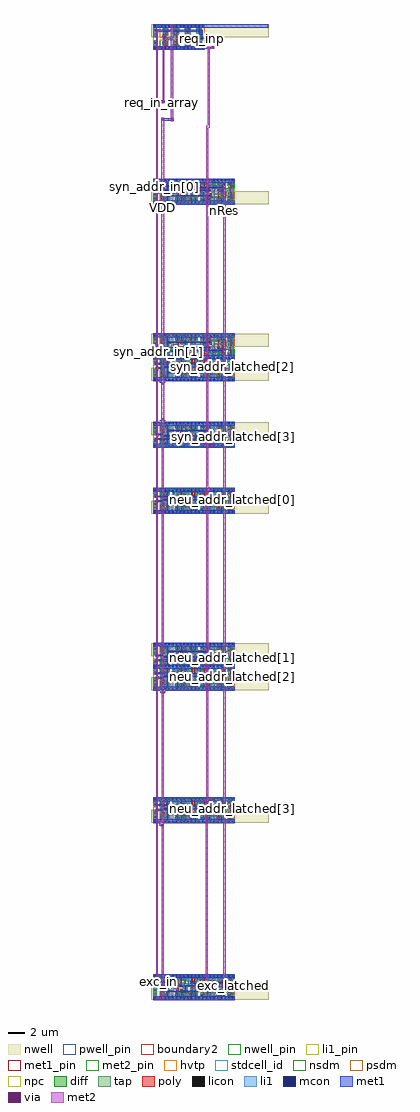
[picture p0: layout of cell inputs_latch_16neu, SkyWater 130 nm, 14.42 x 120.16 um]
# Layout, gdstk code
from math import pi, radians
import gdstk
lib = gdstk.Library(unit=1e-6, precision=1e-09)
def R(c, l, rs):  # rectangles x0, y0, x1, y1
    for r in rs: c.add(gdstk.rectangle(r[:2], r[2:], *l))
def A(c, l, x, y, w, h, nx, ny, dx, dy):  # array of equal rectangles
    R(c, l, [(x+i*dx, y+j*dy, x+i*dx+w, y+j*dy+h) for i in range(nx) for j in range(ny)])
def P(c, l, *ps):  # polygons
    for p in ps: c.add(gdstk.Polygon(p, *l))
nwell_pin = (64, 16)
nwell = (64, 20)
diff = (65, 20)
tap = (65, 44)
poly = (66, 20)
licon = (66, 44)
li1_pin = (67, 16)
li1 = (67, 20)
mcon = (67, 44)
met1_pin = (68, 16)
met1 = (68, 20)
via = (68, 44)
met2_pin = (69, 16)
met2 = (69, 20)
hvtp = (78, 44)
stdcell_id = (81, 4)
nsdm = (93, 44)
psdm = (94, 20)
npc = (95, 20)
pwell_pin = (122, 16)
boundary2 = (236, 0)

sky130_fd_sc_hd__dfrtp_1 = lib.new_cell('sky130_fd_sc_hd__dfrtp_1')
R(sky130_fd_sc_hd__dfrtp_1, nwell_pin, [(0.145,2.635,0.315,2.805)])
R(sky130_fd_sc_hd__dfrtp_1, nwell, [(-0.19,1.305,9.39,2.91)])
R(sky130_fd_sc_hd__dfrtp_1, diff, [(0.135,0.235,1.225,0.655), (0.135,1.815,1.225,2.455), (3.305,2.065,4.7,2.485)])
P(sky130_fd_sc_hd__dfrtp_1, diff, [(8,2.485),(5.015,2.485),(5.015,1.645),(5.695,1.645),(5.695,2.065),(8,2.065)],
  [(9.065,2.485),(8.325,2.485),(8.325,1.845),(8.405,1.845),(8.405,1.485),(9.065,1.485)],
  [(9.065,0.885),(8.405,0.885),(8.405,0.655),(8.295,0.655),(8.295,0.235),(9.065,0.235)],
  [(8.025,0.655),(6.165,0.655),(6.165,0.595),(5.315,0.595),(5.315,0.875),(4.645,0.875),(4.645,0.655),(3.285,0.655),(3.285,0.595),(2.49,0.595),(2.49,0.655),(1.565,0.655),(1.565,0.235),(8.025,0.235)],
  [(3.335,2.485),(1.89,2.485),(1.89,2.065),(3.33,2.065),(3.33,2.48),(3.335,2.48)])
R(sky130_fd_sc_hd__dfrtp_1, poly, [(3.875,0.105,4.025,1.515), (4.29,1.055,4.44,2.615), (3.805,1.445,4.08,1.775), (3.805,1.76,3.955,2.615)])
P(sky130_fd_sc_hd__dfrtp_1, poly, [(7.79,1.825),(7.73,1.825),(7.73,2.615),(7.58,2.615),(7.58,1.825),(7.52,1.825),(7.52,1.495),(7.615,1.495),(7.615,0.105),(7.765,0.105),(7.765,1.495),(7.79,1.495)],
  [(0.545,0.88),(0.38,0.88),(0.38,1.59),(0.545,1.59),(0.545,2.585),(0.395,2.585),(0.395,1.74),(0.23,1.74),(0.23,1.325),(0.11,1.325),(0.11,0.995),(0.23,0.995),(0.23,0.73),(0.395,0.73),(0.395,0.105),(0.545,0.105)],
  [(0.965,2.585),(0.815,2.585),(0.815,1.37),(0.59,1.37),(0.59,1.1),(0.815,1.1),(0.815,0.105),(0.965,0.105)],
  [(2.3,2.615),(2.15,2.615),(2.15,1.63),(1.655,1.63),(1.655,1.3),(2.09,1.3),(2.09,0.105),(2.24,0.105),(2.24,1.48),(2.3,1.48)],
  [(3.255,2.615),(3.105,2.615),(3.105,1.395),(2.565,1.395),(2.565,1.095),(2.45,1.095),(2.45,0.765),(2.565,0.765),(2.565,0.105),(2.715,0.105),(2.715,0.765),(2.72,0.765),(2.72,1.245),(3.255,1.245)],
  [(2.86,1.875),(2.76,1.875),(2.76,2.615),(2.61,2.615),(2.61,1.875),(2.53,1.875),(2.53,1.605),(2.86,1.605)],
  [(3.26,1.035),(2.93,1.035),(2.93,0.765),(3.045,0.765),(3.045,0.105),(3.195,0.105),(3.195,0.765),(3.26,0.765)],
  [(4.505,1.095),(4.235,1.095),(4.235,0.105),(4.385,0.105),(4.385,0.765),(4.505,0.765)],
  [(5.425,2.615),(5.275,2.615),(5.275,1.57),(4.895,1.57),(4.895,1.335),(4.715,1.335),(4.715,1.005),(4.895,1.005),(4.895,0.105),(5.045,0.105),(5.045,1.42),(5.425,1.42)],
  [(5.725,1.035),(5.39,1.035),(5.39,0.105),(5.54,0.105),(5.54,0.705),(5.725,0.705)],
  [(6.205,1.275),(6.085,1.275),(6.085,1.335),(6.02,1.335),(6.02,1.395),(5.92,1.395),(5.92,2.615),(5.77,2.615),(5.77,1.245),(5.875,1.245),(5.875,1.185),(5.935,1.185),(5.935,0.105),(6.085,0.105),(6.085,0.945),(6.205,0.945)],
  [(6.4,1.905),(6.35,1.905),(6.35,2.615),(6.2,2.615),(6.2,1.905),(6.13,1.905),(6.13,1.575),(6.4,1.575)],
  [(6.925,1.145),(6.77,1.145),(6.77,2.615),(6.62,2.615),(6.62,0.965),(6.415,0.965),(6.415,0.105),(6.565,0.105),(6.565,0.815),(6.925,0.815)],
  [(7.405,1.285),(7.31,1.285),(7.31,2.615),(7.16,2.615),(7.16,1.285),(7.135,1.285),(7.135,0.955),(7.16,0.955),(7.16,0.105),(7.31,0.105),(7.31,0.955),(7.405,0.955)],
  [(8.805,2.615),(8.655,2.615),(8.655,1.325),(8.51,1.325),(8.51,0.995),(8.655,0.995),(8.655,0.105),(8.805,0.105)])
R(sky130_fd_sc_hd__dfrtp_1, licon, [(1.625,0.275,1.795,0.445), (5.115,0.275,5.285,0.445), (6.725,0.275,6.895,0.445), (0.595,0.295,0.765,0.465), (4.555,0.295,4.725,0.465), (5.665,0.295,5.835,0.465), (8.435,0.295,8.605,0.465), (2.29,0.305,2.46,0.475), (2.825,0.305,2.995,0.475), (7.815,0.375,7.985,0.545), (0.175,0.425,0.345,0.595), (1.015,0.425,1.185,0.595), (8.855,0.545,9.025,0.715), (5.505,0.785,5.675,0.955), (3.01,0.815,3.18,0.985), (2.5,0.845,2.67,1.015), (4.285,0.845,4.455,1.015), (6.705,0.895,6.875,1.065), (5.985,1.025,6.155,1.195), (7.185,1.035,7.355,1.205), (0.16,1.075,0.33,1.245), (8.56,1.075,8.73,1.245), (4.765,1.085,4.935,1.255), (0.67,1.15,0.84,1.32), (1.705,1.38,1.875,1.55), (3.855,1.525,4.025,1.695), (7.57,1.575,7.74,1.745), (2.61,1.655,2.78,1.825), (6.18,1.655,6.35,1.825), (8.855,1.735,9.025,1.905), (0.175,1.875,0.345,2.045), (1.015,1.875,1.185,2.045), (8.435,1.915,8.605,2.085), (8.855,2.075,9.025,2.245), (3.585,2.125,3.755,2.295), (4.49,2.125,4.66,2.295), (7.36,2.125,7.53,2.295), (0.595,2.135,0.765,2.305), (4.07,2.205,4.24,2.375), (0.175,2.215,0.345,2.385), (1.015,2.215,1.185,2.385), (2.35,2.215,2.52,2.385), (5.495,2.215,5.665,2.385), (2.815,2.245,2.985,2.415), (5.98,2.25,6.15,2.42), (1.93,2.255,2.1,2.425), (5.055,2.255,5.225,2.425), (6.94,2.255,7.11,2.425), (7.79,2.255,7.96,2.425), (8.435,2.255,8.605,2.425)])
A(sky130_fd_sc_hd__dfrtp_1, li1_pin, 8.88, 1.445, 0.17, 0.17, 1, 3, 0, 0.34)
R(sky130_fd_sc_hd__dfrtp_1, li1_pin, [(8.88,0.425,9.05,0.595), (7.405,0.765,7.575,0.935), (0.15,1.105,0.32,1.275), (7.405,1.105,7.575,1.275), (0.15,1.445,0.32,1.615), (1.525,1.445,1.695,1.615)])
R(sky130_fd_sc_hd__dfrtp_1, li1, [(0,-0.085,9.2,0.085), (1.545,-0.03,1.875,0.445), (8.38,0.05,8.685,0.545), (4.475,0.055,4.805,0.545), (0.515,0.06,0.845,0.465), (6.705,0.065,6.895,0.525), (1.015,0.345,1.185,2.465), (1.415,0.615,1.875,1.665), (5.845,0.705,6.195,1.325), (2.385,0.765,2.735,1.385), (3.805,0.765,4.595,1.015), (0.09,0.975,0.44,1.625), (8.38,1.495,8.685,2.71), (3.775,1.525,5.13,1.695), (1.355,1.665,1.68,2.45), (0.515,2.135,0.845,2.665), (4.955,2.175,5.325,2.675), (6.94,2.175,7.19,2.69), (3.99,2.205,4.32,2.69), (7.71,2.255,8.04,2.7)])
P(sky130_fd_sc_hd__dfrtp_1, li1, [(0.84,1.965),(0.345,1.965),(0.345,2.465),(0.09,2.465),(0.09,1.795),(0.61,1.795),(0.61,0.805),(0.09,0.805),(0.09,0.345),(0.345,0.345),(0.345,0.635),(0.84,0.635)],
  [(2.54,0.475),(2.215,0.475),(2.215,1.835),(2.44,1.835),(2.44,2.135),(2.52,2.135),(2.52,2.465),(2.27,2.465),(2.27,2.005),(2.045,2.005),(2.045,0.305),(2.54,0.305)],
  [(3.26,0.985),(3.075,0.985),(3.075,1.965),(2.61,1.965),(2.61,1.575),(2.905,1.575),(2.905,0.765),(3.26,0.765)],
  [(4.935,1.355),(3.415,1.355),(3.415,2.465),(2.735,2.465),(2.735,2.135),(3.245,2.135),(3.245,1.185),(3.43,1.185),(3.43,0.475),(2.745,0.475),(2.745,0.305),(3.6,0.305),(3.6,1.185),(4.765,1.185),(4.765,1.005),(4.935,1.005)],
  [(9.11,2.325),(8.855,2.325),(8.855,1.445),(8.9,1.445),(8.9,0.795),(8.855,0.795),(8.855,0.265),(9.11,0.265)],
  [(5.665,2.465),(5.495,2.465),(5.495,2.005),(5.105,2.005),(5.105,0.835),(5.015,0.835),(5.015,0.275),(5.365,0.275),(5.365,0.445),(5.275,0.445),(5.275,1.835),(5.665,1.835)],
  [(6.43,1.955),(5.97,1.955),(5.97,1.665),(5.465,1.665),(5.465,0.705),(5.675,0.705),(5.675,1.495),(6.14,1.495),(6.14,1.655),(6.43,1.655)],
  [(7.645,1.405),(7.105,1.405),(7.105,1.035),(7.405,1.035),(7.405,0.635),(7.645,0.635)],
  [(7.82,1.745),(6.77,1.745),(6.77,2.465),(5.9,2.465),(5.9,2.125),(6.6,2.125),(6.6,1.485),(6.365,1.485),(6.365,0.535),(5.585,0.535),(5.585,0.255),(6.535,0.255),(6.535,1.315),(6.77,1.315),(6.77,1.575),(7.82,1.575)],
  [(9.2,2.805),(0,2.805),(0,2.635),(1.85,2.635),(1.85,2.175),(2.1,2.175),(2.1,2.635),(9.2,2.635)],
  [(8.73,1.325),(8.16,1.325),(8.16,2.085),(7.53,2.085),(7.53,2.375),(7.36,2.375),(7.36,1.915),(7.99,1.915),(7.99,1.295),(7.815,1.295),(7.815,0.465),(7.235,0.465),(7.235,0.865),(6.925,0.865),(6.925,1.145),(6.705,1.145),(6.705,0.695),(7.065,0.695),(7.065,0.295),(8.135,0.295),(8.135,0.82),(8.14,0.82),(8.14,0.995),(8.73,0.995)],
  [(4.66,2.375),(4.49,2.375),(4.49,2.035),(3.755,2.035),(3.755,2.375),(3.585,2.375),(3.585,1.865),(4.66,1.865)])
A(sky130_fd_sc_hd__dfrtp_1, mcon, 0.145, -0.085, 0.17, 0.17, 20, 2, 0.46, 2.72)
R(sky130_fd_sc_hd__dfrtp_1, mcon, [(3.805,0.765,3.975,0.935), (4.165,0.765,4.335,0.935), (7.405,0.765,7.575,0.935), (7.105,1.08,7.275,1.25), (0.61,1.105,0.78,1.275), (2.445,1.105,2.615,1.275), (6.025,1.105,6.195,1.275), (1.015,1.785,1.185,1.955), (2.905,1.785,3.075,1.955), (6.025,1.785,6.195,1.955)])
R(sky130_fd_sc_hd__dfrtp_1, met1_pin, [(0.145,-0.085,0.315,0.085), (0.145,2.635,0.315,2.805)])
R(sky130_fd_sc_hd__dfrtp_1, met1, [(7.045,0.91,7.335,1.28), (0.55,1.075,0.84,1.305), (5.965,1.075,6.255,1.305), (0.955,1.755,1.245,1.985), (5.965,1.755,6.255,1.985)])
P(sky130_fd_sc_hd__dfrtp_1, met1, [(7.635,0.965),(7.335,0.965),(7.335,0.92),(4.395,0.92),(4.395,0.965),(3.745,0.965),(3.745,0.735),(4.395,0.735),(4.395,0.78),(7.345,0.78),(7.345,0.735),(7.635,0.735)],
  [(6.075,1.94),(3.135,1.94),(3.135,1.985),(2.845,1.985),(2.845,1.94),(1.185,1.94),(1.185,1.8),(2.845,1.8),(2.845,1.755),(3.135,1.755),(3.135,1.8),(6.075,1.8)],
  [(6.045,1.26),(2.675,1.26),(2.675,1.305),(2.385,1.305),(2.385,1.26),(0.82,1.26),(0.82,1.12),(2.385,1.12),(2.385,1.075),(2.675,1.075),(2.675,1.12),(6.045,1.12)])
R(sky130_fd_sc_hd__dfrtp_1, hvtp, [(0,1.25,9.2,2.72)])
R(sky130_fd_sc_hd__dfrtp_1, stdcell_id, [(0,0,9.2,2.72)])
R(sky130_fd_sc_hd__dfrtp_1, nsdm, [(0,-0.19,9.2,1.015)])
P(sky130_fd_sc_hd__dfrtp_1, psdm, [(9.2,2.91),(0,2.91),(0,1.685),(1.35,1.685),(1.35,1.935),(4.885,1.935),(4.885,1.515),(5.825,1.515),(5.825,1.935),(8.155,1.935),(8.155,1.355),(9.2,1.355)])
R(sky130_fd_sc_hd__dfrtp_1, npc, [(3.755,1.365,4.195,1.795)])
P(sky130_fd_sc_hd__dfrtp_1, npc, [(9.2,1.345),(7.84,1.345),(7.84,1.845),(7.47,1.845),(7.47,1.42),(6.45,1.42),(6.45,1.925),(6.08,1.925),(6.08,1.42),(2.88,1.42),(2.88,1.925),(2.51,1.925),(2.51,1.65),(1.6,1.65),(1.6,1.42),(0.565,1.42),(0.565,1.345),(0,1.345),(0,0.975),(1.425,0.975),(1.425,0.745),(2.91,0.745),(2.91,0.715),(3.28,0.715),(3.28,1.05),(4.185,1.05),(4.185,0.745),(4.555,0.745),(4.555,0.985),(5.055,0.985),(5.055,1.05),(5.405,1.05),(5.405,0.685),(5.775,0.685),(5.775,0.925),(6.605,0.925),(6.605,0.795),(6.975,0.795),(6.975,0.935),(7.455,0.935),(7.455,0.975),(9.2,0.975)])
R(sky130_fd_sc_hd__dfrtp_1, pwell_pin, [(0.145,-0.085,0.315,0.085)])
R(sky130_fd_sc_hd__dfrtp_1, boundary2, [(0,0,9.2,2.72)])
sky130_fd_sc_hd__dfrtp_1.add(gdstk.FlexPath([(0,0),(9.2,0)], 0.48, ends="flush", simple_path=True, layer=68, datatype=20))  # met1
sky130_fd_sc_hd__dfrtp_1.add(gdstk.FlexPath([(0,2.72),(9.2,2.72)], 0.48, ends="flush", simple_path=True, layer=68, datatype=20))  # met1
sky130_fd_sc_hd__dfrtp_1.add(gdstk.Label('Q', (8.965,2.21), layer=67, texttype=5))
sky130_fd_sc_hd__dfrtp_1.add(gdstk.Label('Q', (8.965,1.87), layer=67, texttype=5))
sky130_fd_sc_hd__dfrtp_1.add(gdstk.Label('Q', (8.965,1.53), layer=67, texttype=5))
sky130_fd_sc_hd__dfrtp_1.add(gdstk.Label('Q', (8.965,0.51), layer=67, texttype=5))
sky130_fd_sc_hd__dfrtp_1.add(gdstk.Label('RESET_B', (7.49,0.85), layer=67, texttype=5))
sky130_fd_sc_hd__dfrtp_1.add(gdstk.Label('D', (1.61,1.53), layer=67, texttype=5))
sky130_fd_sc_hd__dfrtp_1.add(gdstk.Label('CLK', (0.235,1.53), layer=67, texttype=5))
sky130_fd_sc_hd__dfrtp_1.add(gdstk.Label('CLK', (0.235,1.19), layer=67, texttype=5))
sky130_fd_sc_hd__dfrtp_1.add(gdstk.Label('RESET_B', (7.49,1.19), layer=67, texttype=5))
sky130_fd_sc_hd__dfrtp_1.add(gdstk.Label('VGND', (0.23,0), layer=68, texttype=5))
sky130_fd_sc_hd__dfrtp_1.add(gdstk.Label('VPWR', (0.23,2.72), layer=68, texttype=5))
sky130_fd_sc_hd__dfrtp_1.add(gdstk.Label('VPB', (0.23,2.72), layer=64, texttype=5))
sky130_fd_sc_hd__dfrtp_1.add(gdstk.Label('VNB', (0.23,0), layer=64, texttype=59))
sky130_fd_sc_hd__dfrtp_1.add(gdstk.Label('dfrtp_1', (0,0), layer=83, texttype=44))

sky130_fd_sc_hd__tapvpwr = lib.new_cell('sky130_fd_sc_hd__tapvpwrvgnd_1')
R(sky130_fd_sc_hd__tapvpwr, nwell, [(-0.19,1.305,0.65,2.91)])
R(sky130_fd_sc_hd__tapvpwr, tap, [(0.145,0.32,0.315,0.845), (0.145,1.525,0.315,2.4)])
R(sky130_fd_sc_hd__tapvpwr, licon, [(0.145,0.555,0.315,0.725), (0.145,1.645,0.315,1.815), (0.145,2.11,0.315,2.28)])
R(sky130_fd_sc_hd__tapvpwr, li1, [(0,-0.085,0.46,0.085), (0.085,0,0.375,0.81), (0.085,1.47,0.375,2.72), (0,2.635,0.46,2.805)])
R(sky130_fd_sc_hd__tapvpwr, mcon, [(0.145,-0.085,0.315,0.085), (0.145,2.635,0.315,2.805)])
R(sky130_fd_sc_hd__tapvpwr, met1_pin, [(0.105,-0.09,0.36,0.1), (0.11,2.62,0.375,2.765)])
R(sky130_fd_sc_hd__tapvpwr, met1, [(0,-0.24,0.46,0.24), (0,2.48,0.46,2.96)])
R(sky130_fd_sc_hd__tapvpwr, hvtp, [(0,1.25,0.46,2.72)])
R(sky130_fd_sc_hd__tapvpwr, stdcell_id, [(0,0,0.46,2.72)])
R(sky130_fd_sc_hd__tapvpwr, nsdm, [(0,-0.19,0.46,0.19), (0,1.395,0.46,2.53)])
R(sky130_fd_sc_hd__tapvpwr, psdm, [(0,0.19,0.46,0.975), (0,2.53,0.46,2.91)])
sky130_fd_sc_hd__tapvpwr.add(gdstk.Label('VPWR', (0.23,2.72), layer=68, texttype=5))
sky130_fd_sc_hd__tapvpwr.add(gdstk.Label('VGND', (0.23,0), layer=68, texttype=5))
sky130_fd_sc_hd__tapvpwr.add(gdstk.Label('tapvpwrvgnd_1', (0,0), layer=83, texttype=44))

sky130_fd_sc_hd__inv_1 = lib.new_cell('sky130_fd_sc_hd__inv_1')
R(sky130_fd_sc_hd__inv_1, nwell_pin, [(0.145,2.635,0.315,2.805), (0.145,2.635,0.315,2.805)])
R(sky130_fd_sc_hd__inv_1, nwell, [(-0.19,1.305,1.57,2.91)])
R(sky130_fd_sc_hd__inv_1, diff, [(0.34,0.235,1.01,0.885), (0.34,1.485,1.01,2.485)])
P(sky130_fd_sc_hd__inv_1, poly, [(0.75,2.615),(0.6,2.615),(0.6,1.325),(0.32,1.325),(0.32,0.995),(0.6,0.995),(0.6,0.105),(0.75,0.105)])
A(sky130_fd_sc_hd__inv_1, licon, 0.38, 1.575, 0.17, 0.17, 1, 3, 0, 0.34)
A(sky130_fd_sc_hd__inv_1, licon, 0.8, 1.575, 0.17, 0.17, 1, 3, 0, 0.34)
R(sky130_fd_sc_hd__inv_1, licon, [(0.38,0.315,0.55,0.485), (0.8,0.315,0.97,0.485), (0.38,0.655,0.55,0.825), (0.8,0.655,0.97,0.825), (0.4,1.075,0.57,1.245)])
R(sky130_fd_sc_hd__inv_1, li1_pin, [(0.36,1.105,0.53,1.275), (0.82,1.105,0.99,1.275), (0.82,1.445,0.99,1.615)])
R(sky130_fd_sc_hd__inv_1, li1, [(0,-0.085,1.38,0.085), (0.32,0.005,0.55,0.905), (0.32,1.075,0.65,1.315), (0.34,1.495,0.55,2.675), (0,2.635,1.38,2.805)])
P(sky130_fd_sc_hd__inv_1, li1, [(1.05,2.465),(0.72,2.465),(0.72,1.485),(0.82,1.485),(0.82,0.885),(0.72,0.885),(0.72,0.255),(1.05,0.255)])
A(sky130_fd_sc_hd__inv_1, mcon, 0.145, -0.085, 0.17, 0.17, 3, 2, 0.46, 2.72)
R(sky130_fd_sc_hd__inv_1, met1_pin, [(0.145,-0.085,0.315,0.085), (0.145,-0.085,0.315,0.085), (0.145,2.635,0.315,2.805), (0.145,2.635,0.315,2.805)])
R(sky130_fd_sc_hd__inv_1, hvtp, [(0,1.25,1.38,2.72)])
R(sky130_fd_sc_hd__inv_1, stdcell_id, [(0,0,1.38,2.72)])
R(sky130_fd_sc_hd__inv_1, nsdm, [(0,-0.19,1.38,1.015)])
R(sky130_fd_sc_hd__inv_1, psdm, [(0,1.355,1.38,2.91)])
R(sky130_fd_sc_hd__inv_1, npc, [(0,0.975,1.38,1.345)])
R(sky130_fd_sc_hd__inv_1, pwell_pin, [(0.145,-0.085,0.315,0.085), (0.145,-0.085,0.315,0.085)])
R(sky130_fd_sc_hd__inv_1, boundary2, [(0,0,1.38,2.72)])
sky130_fd_sc_hd__inv_1.add(gdstk.FlexPath([(0,2.72),(1.38,2.72)], 0.48, ends="flush", simple_path=True, layer=68, datatype=20))  # met1
sky130_fd_sc_hd__inv_1.add(gdstk.FlexPath([(0,0),(1.38,0)], 0.48, ends="flush", simple_path=True, layer=68, datatype=20))  # met1
sky130_fd_sc_hd__inv_1.add(gdstk.Label('Y', (0.905,1.53), layer=67, texttype=5))
sky130_fd_sc_hd__inv_1.add(gdstk.Label('Y', (0.905,1.19), layer=67, texttype=5))
sky130_fd_sc_hd__inv_1.add(gdstk.Label('A', (0.445,1.19), layer=67, texttype=5))
sky130_fd_sc_hd__inv_1.add(gdstk.Label('VPB', (0.23,2.72), layer=64, texttype=5))
sky130_fd_sc_hd__inv_1.add(gdstk.Label('VNB', (0.23,0), layer=64, texttype=59))
sky130_fd_sc_hd__inv_1.add(gdstk.Label('VGND', (0.23,0), layer=68, texttype=5))
sky130_fd_sc_hd__inv_1.add(gdstk.Label('VPWR', (0.23,2.72), layer=68, texttype=5))
sky130_fd_sc_hd__inv_1.add(gdstk.Label('inv_1', (0,0), layer=83, texttype=44))

inputs_latch_16neu = lib.new_cell('inputs_latch_16neu')
R(inputs_latch_16neu, nwell, [(90.575,-75.35,96.175,-73.745), (90.575,-53.59,96.175,-51.985), (90.575,-37.27,96.175,-35.665), (90.575,-33.055,96.175,-31.45), (90.575,-15.51,96.175,-13.905), (90.575,-5.855,96.175,-4.25), (90.575,0.81,96.175,2.415), (90.575,5.025,96.175,6.63), (90.575,22.57,96.175,24.175), (86.895,43.105,96.175,44.71)])
R(inputs_latch_16neu, li1_pin, [(91.825,-73.69,91.89,-73.66), (91.76,-51.86,91.8,-51.775), (91.73,-35.63,91.77,-35.545), (91.775,-33.255,91.815,-33.17), (91.72,-13.815,91.76,-13.73), (91.785,-6.085,91.825,-6), (91.76,2.525,91.8,2.61), (91.81,4.825,91.85,4.91), (91.735,24.255,91.745,24.295), (88.05,42.965,88.11,43.025)])
A(inputs_latch_16neu, li1, 82.355, -34.445, 0.515, 0.17, 1, 3, 0, 38.08)
A(inputs_latch_16neu, li1, 82.305, -4.525, 0.575, 0.17, 1, 3, 0, 5.44)
R(inputs_latch_16neu, li1, [(82.32,-75.245,82.88,-75.075), (84.315,-74.015,84.555,-73.155), (82.775,-73.985,83.185,-73.775), (91.69,-73.795,91.9,-73.755), (82.455,-73.775,83.185,-73.55), (91.69,-73.755,92.05,-73.545), (82.775,-73.55,83.145,-73.53), (91.69,-73.545,91.9,-73.35), (82.775,-73.53,83,-73.46), (84.33,-73.155,84.54,-73.06), (82.38,-72.525,82.87,-72.345), (82.305,-53.485,82.88,-53.315), (84.275,-52.14,84.6,-51.375), (82.9,-52.07,83.075,-51.895), (91.69,-52.035,91.9,-51.585), (84.335,-51.375,84.54,-51.315), (82.355,-50.765,82.87,-50.585), (82.305,-37.165,82.88,-36.995), (84.29,-35.95,84.58,-35.18), (82.89,-35.825,83.06,-35.655), (91.69,-35.715,91.9,-35.285), (84.31,-35.18,84.56,-35.025), (84.32,-33.695,84.55,-33.68), (84.29,-33.68,84.58,-32.97), (91.69,-33.41,91.9,-33.01), (82.96,-33.235,83.035,-33.07), (82.935,-33.07,83.105,-32.9), (84.32,-32.97,84.55,-32.94), (82.96,-32.9,83.035,-32.86), (82.305,-31.725,82.88,-31.55), (82.305,-15.405,82.88,-15.235), (84.285,-14.24,84.585,-13.245), (82.905,-14.09,83.05,-14.05), (82.905,-14.05,83.09,-13.88), (91.69,-13.935,91.9,-13.55), (82.905,-13.88,83.05,-13.71), (82.355,-12.685,82.87,-12.505), (82.355,-7.255,82.87,-7.075), (84.3,-6.5,84.575,-5.545), (91.69,-6.315,91.9,-5.78), (82.885,-6.005,83.03,-5.87), (82.885,-5.87,83.115,-5.7), (82.885,-5.7,83.03,-5.62), (84.29,2.07,84.585,3.09), (82.87,2.19,83.115,2.56), (91.69,2.405,91.9,2.945), (84.33,4.355,84.54,4.94), (91.69,4.715,91.9,5.075), (82.885,4.865,83.12,5.015), (82.885,5.015,83.13,5.2), (82.885,5.2,83.12,5.22), (82.275,22.675,82.89,22.7), (82.275,22.7,82.935,22.81), (82.315,22.81,82.935,22.845), (82.545,23.885,83.23,24.235), (90.265,24.15,90.435,24.54), (91.69,24.155,91.9,24.595), (90.895,24.205,91.34,24.44), (82.545,24.235,82.895,24.46), (84.365,24.505,84.51,24.56), (84.285,24.56,84.605,24.57), (84.285,24.57,84.63,24.735), (84.285,24.735,84.605,24.745), (82.275,25.395,82.88,25.42), (82.275,25.42,82.935,25.53), (82.365,25.53,82.935,25.565), (82.86,35.06,83.29,35.285), (83.155,42.32,83.325,42.49), (83.12,42.625,83.35,43.335), (87.24,42.85,87.32,42.875), (86.53,42.875,87.33,42.955), (85.18,42.88,86.05,42.96), (83.79,42.89,84.57,43), (87.93,42.92,88.24,42.925), (87.855,42.925,88.24,42.97), (86.55,42.955,87.32,43), (85.18,42.96,85.92,43.02), (85.97,42.96,86.05,43.12), (87.66,42.97,88.24,43.05), (83.77,43,84.57,43.03), (86.55,43,87.29,43.035), (85.15,43.02,85.92,43.1), (83.76,43.03,84.57,43.08), (86.53,43.035,87.29,43.115), (87.855,43.05,88.24,43.09), (83.76,43.08,84.51,43.11), (87.855,43.09,88.025,43.095), (87.93,43.095,87.985,43.1), (82.305,44.425,82.88,44.605)])
R(inputs_latch_16neu, mcon, [(82.94,-73.76,83.11,-73.59), (82.48,-73.75,82.65,-73.58), (84.35,-73.25,84.52,-73.08), (82.9,-52.07,83.07,-51.9), (84.35,-51.505,84.52,-51.335), (82.89,-35.825,83.06,-35.655), (84.35,-35.235,84.52,-35.065), (84.35,-33.665,84.52,-33.495), (82.935,-33.07,83.105,-32.9), (82.92,-14.05,83.09,-13.88), (84.35,-13.49,84.52,-13.32), (84.35,-6.45,84.52,-6.28), (82.945,-5.87,83.115,-5.7), (82.945,2.325,83.115,2.495), (84.35,2.855,84.52,3.025), (84.35,4.375,84.52,4.545), (82.95,5.02,83.12,5.19), (82.635,24.045,82.805,24.215), (90.265,24.15,90.435,24.32), (84.425,24.565,84.595,24.735), (82.885,35.085,83.055,35.255), (83.155,42.32,83.325,42.49), (87.855,42.925,88.025,43.095), (83.15,43.135,83.32,43.305)])
R(inputs_latch_16neu, met1_pin, [(82.63,-73.19,82.7,-73.13), (82.64,-51.47,82.665,-51.435), (82.67,-35.255,82.725,-35.17), (82.66,-33.64,82.715,-33.555), (82.685,-13.44,82.74,-13.355), (82.635,-6.415,82.69,-6.33), (82.685,2.875,82.74,2.96), (82.63,4.415,82.65,4.425), (82.08,24.76,82.12,24.81), (82.905,35.11,82.99,35.175)])
R(inputs_latch_16neu, met1, [(82.15,-75.4,82.885,-75.315), (82.15,-75.315,82.89,-75.285), (82.15,-75.285,82.935,-75.13), (83.545,-75.27,83.82,-75.24), (82.31,-75.13,82.935,-75.075), (82.31,-75.075,82.965,-75.025), (82.335,-75.025,82.965,-74.92), (83.545,-74.965,83.82,-74.935), (82.555,-73.935,83.16,-73.83), (82.44,-73.83,83.16,-73.79), (89.845,-73.8,90.915,-73.51), (82.44,-73.79,83.17,-73.78), (82.42,-73.78,83.17,-73.56), (82.42,-73.56,83.16,-73.555), (82.42,-73.555,83.125,-73.55), (82.44,-73.55,83.125,-73.535), (82.44,-73.535,83.09,-73.51), (82.555,-73.51,83.09,-73.415), (89.845,-73.51,90.885,-73.32), (84.27,-73.3,84.6,-73.27), (82.6,-73.27,84.6,-73.06), (84.27,-73.06,84.6,-73.03), (82.295,-72.68,82.87,-72.525), (88.405,-72.61,88.725,-72.35), (82.405,-72.525,82.79,-72.355), (82.3,-72.355,82.925,-72.2), (82.89,-54,83.15,-53.71), (82.89,-53.71,83.285,-53.69), (82.76,-53.69,83.285,-53.64), (81.95,-53.64,83.31,-53.485), (83.55,-53.565,83.825,-53.23), (82.27,-53.485,83.31,-53.365), (82.27,-53.365,83.095,-53.315), (81.95,-53.315,83.095,-53.16), (82.295,-52.125,82.615,-52.1), (82.295,-52.1,83.135,-51.865), (89.915,-51.98,90.915,-51.69), (89.915,-51.69,90.75,-51.515), (84.275,-51.55,84.6,-51.515), (82.295,-51.515,84.6,-51.31), (84.275,-51.31,84.6,-51.285), (81.95,-50.92,82.87,-50.765), (89.005,-50.885,89.265,-50.565), (82.28,-50.765,82.86,-50.595), (81.95,-50.595,82.925,-50.44), (82.975,-37.66,83.31,-37.57), (82.83,-37.57,83.445,-37.32), (81.95,-37.32,83.445,-37.165), (82.315,-37.165,82.825,-36.995), (82.83,-37.165,83.445,-37.1), (81.95,-36.995,82.965,-36.84), (82.345,-35.9,82.575,-35.89), (82.295,-35.89,82.615,-35.855), (82.295,-35.855,83.12,-35.63), (82.345,-35.63,82.575,-35.61), (82.83,-35.63,83.12,-35.625), (82.345,-35.61,82.57,-35.46), (89.945,-35.435,90.915,-35.145), (84.25,-35.305,84.62,-35.275), (82.23,-35.275,84.62,-35.025), (84.25,-35.025,84.62,-34.995), (81.95,-34.6,82.87,-34.595), (81.95,-34.595,82.925,-34.445), (88.455,-34.465,88.775,-34.205), (82.305,-34.445,82.925,-34.44), (82.305,-34.44,82.885,-34.275), (81.95,-34.275,82.925,-34.12), (84.26,-33.725,84.61,-33.695), (82.26,-33.695,84.61,-33.465), (90.04,-33.555,90.735,-33.37), (84.26,-33.465,84.61,-33.435), (90.04,-33.37,90.915,-33.08), (82.345,-33.24,82.57,-33.12), (82.345,-33.12,82.575,-33.115), (82.295,-33.115,82.615,-33.09), (82.875,-33.1,83.165,-33.09), (82.295,-33.09,83.165,-32.88), (82.295,-32.88,82.615,-32.855), (82.875,-32.88,83.165,-32.87), (82.345,-32.855,82.575,-32.83), (81.95,-31.875,82.965,-31.72), (82.975,-31.87,83.31,-31.595), (82.285,-31.72,82.925,-31.55), (81.95,-31.55,82.925,-31.495), (81.95,-31.495,82.885,-31.395), (81.95,-15.56,82.885,-15.405), (83.005,-15.55,83.28,-15.52), (82.975,-15.52,83.31,-15.245), (82.175,-15.405,82.805,-15.235), (83.005,-15.245,83.28,-15.215), (81.95,-15.235,82.965,-15.08), (82.345,-14.125,82.575,-14.075), (82.86,-14.08,83.15,-14.065), (82.295,-14.075,82.615,-14.065), (82.295,-14.065,83.15,-13.87), (82.295,-13.87,82.615,-13.815), (82.86,-13.87,83.15,-13.85), (82.345,-13.815,82.57,-13.705), (89.945,-13.79,90.915,-13.5), (84.235,-13.575,84.64,-13.495), (82.24,-13.495,84.64,-13.305), (84.235,-13.305,84.64,-13.23), (81.95,-12.84,82.87,-12.685), (88.87,-12.73,89.13,-12.41), (82.28,-12.685,82.86,-12.515), (81.95,-12.515,82.925,-12.36), (81.95,-7.4,82.925,-7.245), (89.165,-7.34,89.425,-7.02), (88.78,-7.31,89.04,-7.28), (88.6,-7.275,88.78,-7.025), (82.28,-7.245,82.795,-7.075), (81.95,-7.075,82.87,-6.92), (88.78,-7.02,89.04,-6.99), (84.24,-6.53,84.635,-6.455), (82.24,-6.455,84.635,-6.265), (89.94,-6.385,90.915,-6.095), (84.24,-6.265,84.635,-6.195), (82.345,-6.045,82.57,-5.89), (82.885,-5.9,83.175,-5.885), (82.295,-5.89,82.615,-5.885), (82.295,-5.885,83.175,-5.69), (82.295,-5.69,82.615,-5.63), (82.885,-5.69,83.175,-5.67), (82.345,-5.63,82.575,-5.59), (81.95,-4.68,82.965,-4.525), (83.415,-4.615,83.75,-4.585), (82.99,-4.585,83.75,-4.36), (82.26,-4.525,82.81,-4.455), (82.26,-4.455,82.955,-4.36), (82.26,-4.36,83.75,-4.355), (81.95,-4.355,83.75,-4.22), (81.95,-4.22,83.48,-4.2), (82.79,-4.2,83.48,-4.025), (82.945,-4.025,83.34,-3.755), (82.945,0.36,83.34,0.62), (82.805,0.62,83.48,0.76), (81.95,0.76,83.48,0.915), (82.275,0.915,83.48,0.955), (82.275,0.955,83.07,1.025), (82.275,1.025,82.8,1.085), (81.95,1.085,82.965,1.24), (82.345,2.095,82.57,2.295), (82.345,2.295,83.175,2.305), (82.295,2.305,83.175,2.525), (90.035,2.49,90.915,2.78), (82.295,2.525,82.615,2.565), (82.345,2.565,82.575,2.59), (84.23,2.765,84.645,2.815), (82.2,2.815,84.645,3.065), (84.23,3.065,84.645,3.12), (81.95,3.48,82.925,3.635), (88.455,3.505,88.775,3.765), (82.24,3.635,82.79,3.685), (82.24,3.685,83.03,3.805), (81.95,3.805,83.03,3.84), (81.95,3.84,82.925,3.96), (84.27,4.325,84.6,4.355), (82.2,4.355,84.6,4.565), (89.965,4.525,90.915,4.815), (84.27,4.565,84.6,4.595), (82.345,4.86,82.57,4.96), (82.345,4.96,82.575,4.985), (82.295,4.985,83.19,5.23), (82.295,5.23,82.615,5.245), (82.345,5.245,82.575,5.25), (81.95,6.2,82.965,6.24), (81.95,6.24,83.34,6.355), (82.25,6.355,83.34,6.425), (82.24,6.425,83.34,6.525), (81.95,6.525,83.34,6.575), (81.95,6.575,83.035,6.58), (81.95,6.58,82.885,6.68), (82.235,22.52,82.895,22.605), (82.975,22.575,83.31,22.605), (82.19,22.605,83.34,22.87), (82.245,22.87,83.34,22.94), (82.245,22.94,83.31,22.97), (82.245,22.97,83.075,22.99), (82.245,22.99,82.975,23), (82.55,23.99,82.895,24.005), (82.29,24.005,82.895,24.265), (90.125,24.1,90.415,24.12), (90.125,24.12,90.495,24.15), (90.125,24.15,90.595,24.41), (82.55,24.265,82.895,24.275), (89.835,24.41,90.915,24.7), (84.39,24.5,84.635,24.725), (81.985,24.725,84.635,24.805), (81.985,24.805,84.605,24.91), (82.21,25.245,82.88,25.4), (88.91,25.37,89.17,25.69), (82.21,25.4,82.85,25.445), (82.21,25.445,83.04,25.6), (82.235,25.6,82.89,25.72), (82.945,32.83,84.48,33.165), (82.83,35,83.115,35.045), (82.83,35.045,83.39,35.305), (82.83,35.305,83.115,35.345), (81.95,41.56,82.925,41.585), (81.95,41.585,82.965,41.715), (89.21,41.695,89.47,41.73), (82.17,41.715,82.965,41.73), (82.17,41.73,89.47,41.885), (81.95,41.885,89.47,41.98), (81.95,41.98,82.87,42.04), (89.21,41.98,89.47,42.015), (83.125,42.26,83.355,42.275), (83.075,42.275,83.395,42.535), (83.125,42.535,83.355,42.55), (83.125,42.55,83.35,43.075), (87.825,42.865,88.055,43.155), (83.06,43.075,83.41,43.365), (87.825,43.155,88.05,43.82), (83.125,43.365,83.35,43.495), (82.295,43.8,82.615,43.82), (82.295,43.82,88.05,44.045), (82.295,44.045,82.615,44.06), (81.95,44.28,96.145,44.435), (82.02,44.435,96.145,44.605), (81.95,44.605,96.145,44.76)])
R(inputs_latch_16neu, via, [(82.675,-75.225,82.825,-75.075), (82.495,-73.745,82.645,-73.595), (90.665,-73.73,90.815,-73.58), (88.49,-72.555,88.64,-72.405), (82.945,-53.915,83.095,-53.765), (83.065,-53.58,83.215,-53.43), (82.38,-52.07,82.53,-51.92), (90.665,-51.91,90.815,-51.76), (89.06,-50.8,89.21,-50.65), (83.065,-37.6,83.215,-37.45), (82.38,-35.835,82.53,-35.685), (90.665,-35.365,90.815,-35.215), (88.54,-34.41,88.69,-34.26), (90.665,-33.3,90.815,-33.15), (82.38,-33.06,82.53,-32.91), (83.065,-31.81,83.215,-31.66), (83.065,-15.46,83.215,-15.31), (82.38,-14.02,82.53,-13.87), (90.665,-13.72,90.815,-13.57), (88.925,-12.645,89.075,-12.495), (89.22,-7.255,89.37,-7.105), (90.665,-6.315,90.815,-6.165), (82.38,-5.835,82.53,-5.685), (83.065,-4,83.215,-3.85), (83.065,0.45,83.215,0.6), (82.38,2.36,82.53,2.51), (90.665,2.56,90.815,2.71), (88.54,3.56,88.69,3.71), (90.665,4.595,90.815,4.745), (82.38,5.04,82.53,5.19), (83.065,6.33,83.215,6.48), (83.065,22.695,83.215,22.845), (82.375,24.06,82.525,24.21), (90.665,24.48,90.815,24.63), (88.965,25.455,89.115,25.605), (83.065,32.92,83.215,33.07), (84.205,32.92,84.355,33.07), (83.155,35.1,83.305,35.25), (89.265,41.78,89.415,41.93), (83.16,42.33,83.31,42.48), (83.16,43.155,83.31,43.305), (82.38,43.855,82.53,44.005), (84.205,44.44,84.355,44.59)])
R(inputs_latch_16neu, met2_pin, [(90.64,21.75,90.78,21.845), (88.585,22,88.625,22.035), (83.045,22.185,83.085,22.22)])
R(inputs_latch_16neu, met2, [(82.435,-75.285,83.28,-75.01), (83.005,-75.01,83.28,-53.97), (82.33,-73.86,82.71,-73.635), (90.595,-73.83,90.885,24.73), (82.34,-73.635,82.71,-73.51), (82.34,-73.51,82.565,-52.155), (88.435,-72.64,88.695,-72.32), (88.44,-72.32,88.69,-50.85), (82.86,-53.97,83.28,-53.93), (82.73,-53.93,83.28,-53.535), (82.73,-53.535,83.325,-53.32), (82.82,-53.32,83.325,-53.275), (83.005,-53.275,83.325,-53.26), (83.005,-53.26,83.28,-37.21), (82.325,-52.155,82.585,-51.835), (82.34,-51.835,82.565,-35.92), (88.975,-50.855,89.295,-50.85), (88.44,-50.85,89.295,-50.6), (88.49,-50.6,88.74,-34.495), (88.975,-50.6,89.295,-50.595), (83.005,-37.21,83.295,-36.935), (83.005,-36.935,83.28,-15.52), (82.325,-35.92,82.585,-35.6), (82.34,-35.6,82.565,-33.145), (88.485,-34.495,88.745,-34.175), (88.49,-34.175,88.74,-12.865), (82.325,-33.145,82.585,-32.825), (82.34,-32.825,82.565,-14.105), (82.975,-15.52,83.31,-15.245), (83.005,-15.245,83.28,-4.73), (82.325,-14.105,82.585,-13.785), (82.34,-13.785,82.565,-5.92), (88.49,-12.865,88.9,-12.7), (88.49,-12.7,89.16,-12.44), (88.49,-12.44,88.9,-12.205), (88.49,-12.205,88.74,-7.425), (88.49,-7.425,88.755,-7.305), (89.135,-7.31,89.455,-7.305), (88.49,-7.305,89.455,-7.055), (88.49,-7.055,88.755,-6.87), (89.135,-7.055,89.455,-7.05), (88.49,-6.87,88.74,3.475), (82.325,-5.92,82.585,-5.6), (82.34,-5.6,82.565,2.275), (82.975,-4.73,83.31,-4.585), (82.975,-4.585,83.335,-4.25), (82.975,-4.25,83.31,0.795), (82.975,0.795,83.32,1.13), (82.975,1.13,83.31,22.605), (82.325,2.275,82.585,2.595), (82.34,2.595,82.565,4.955), (88.485,3.475,88.745,3.795), (88.49,3.795,88.74,25.225), (82.325,4.955,82.585,5.275), (82.34,5.275,82.565,23.975), (82.945,22.605,83.34,22.94), (82.975,22.94,83.31,33.24), (82.32,23.975,82.58,24.295), (82.34,24.295,82.565,43.77), (88.49,25.225,89.185,25.4), (88.49,25.4,89.2,25.655), (88.49,25.655,88.74,31.985), (88.88,25.655,89.2,25.66), (88.49,31.985,88.93,32.235), (88.68,32.235,88.93,41.73), (84.115,32.8,84.45,44.715), (83.1,35.015,83.36,35.335), (83.12,35.335,83.345,42.245), (89.18,41.725,89.5,41.73), (88.68,41.73,89.5,41.98), (89.18,41.98,89.5,41.985), (83.105,42.245,83.365,42.565), (83.12,42.565,83.345,43.07), (83.105,43.07,83.365,43.39), (82.325,43.77,82.585,44.09)])
R(inputs_latch_16neu, nsdm, [(82.8,-34.47,91.98,-34.25), (82.8,3.61,91.98,3.83)])
inputs_latch_16neu.add(gdstk.Reference(sky130_fd_sc_hd__dfrtp_1, (82.79,-72.44), x_reflection=True))
inputs_latch_16neu.add(gdstk.Reference(sky130_fd_sc_hd__tapvpwr, (81.95,-72.44), x_reflection=True))
inputs_latch_16neu.add(gdstk.Reference(sky130_fd_sc_hd__dfrtp_1, (82.79,-50.68), x_reflection=True))
inputs_latch_16neu.add(gdstk.Reference(sky130_fd_sc_hd__tapvpwr, (81.95,-50.68), x_reflection=True))
inputs_latch_16neu.add(gdstk.Reference(sky130_fd_sc_hd__dfrtp_1, (82.79,-34.36)))
inputs_latch_16neu.add(gdstk.Reference(sky130_fd_sc_hd__dfrtp_1, (82.79,-34.36), x_reflection=True))
inputs_latch_16neu.add(gdstk.Reference(sky130_fd_sc_hd__tapvpwr, (81.95,-34.36)))
inputs_latch_16neu.add(gdstk.Reference(sky130_fd_sc_hd__tapvpwr, (81.95,-34.36), x_reflection=True))
inputs_latch_16neu.add(gdstk.Reference(sky130_fd_sc_hd__dfrtp_1, (82.79,-12.6), x_reflection=True))
inputs_latch_16neu.add(gdstk.Reference(sky130_fd_sc_hd__tapvpwr, (81.95,-12.6), x_reflection=True))
inputs_latch_16neu.add(gdstk.Reference(sky130_fd_sc_hd__dfrtp_1, (82.79,-7.16)))
inputs_latch_16neu.add(gdstk.Reference(sky130_fd_sc_hd__tapvpwr, (81.95,-7.16)))
inputs_latch_16neu.add(gdstk.Reference(sky130_fd_sc_hd__dfrtp_1, (82.79,3.72), x_reflection=True))
inputs_latch_16neu.add(gdstk.Reference(sky130_fd_sc_hd__tapvpwr, (81.95,3.72), x_reflection=True))
inputs_latch_16neu.add(gdstk.Reference(sky130_fd_sc_hd__dfrtp_1, (82.79,3.72)))
inputs_latch_16neu.add(gdstk.Reference(sky130_fd_sc_hd__tapvpwr, (81.95,3.72)))
inputs_latch_16neu.add(gdstk.Reference(sky130_fd_sc_hd__dfrtp_1, (82.79,25.48), x_reflection=True))
inputs_latch_16neu.add(gdstk.Reference(sky130_fd_sc_hd__tapvpwr, (81.95,25.48), x_reflection=True))
inputs_latch_16neu.add(gdstk.Reference(sky130_fd_sc_hd__inv_1, (84.17,41.8), rotation=pi, x_reflection=True))
inputs_latch_16neu.add(gdstk.Reference(sky130_fd_sc_hd__inv_1, (85.55,41.8), rotation=pi, x_reflection=True))
inputs_latch_16neu.add(gdstk.Reference(sky130_fd_sc_hd__inv_1, (86.93,41.8), rotation=pi, x_reflection=True))
inputs_latch_16neu.add(gdstk.Reference(sky130_fd_sc_hd__inv_1, (88.31,41.8), rotation=pi, x_reflection=True))
inputs_latch_16neu.add(gdstk.Reference(sky130_fd_sc_hd__tapvpwr, (81.95,41.8)))
inputs_latch_16neu.add(gdstk.Label('req_inp', (88.08,42.995), layer=67, texttype=5))
inputs_latch_16neu.add(gdstk.Label('nRes', (90.71,21.797), layer=69, texttype=5))
inputs_latch_16neu.add(gdstk.Label('syn_addr_in[0]', (82.1,24.785), layer=68, texttype=5))
inputs_latch_16neu.add(gdstk.Label('syn_addr_latched[0]', (91.74,24.275), layer=67, texttype=5))
inputs_latch_16neu.add(gdstk.Label('syn_addr_in[1]', (82.64,4.42), layer=68, texttype=5))
inputs_latch_16neu.add(gdstk.Label('syn_addr_latched[1]', (91.83,4.867), layer=67, texttype=5))
inputs_latch_16neu.add(gdstk.Label('syn_addr_latched[2]', (91.78,2.567), layer=67, texttype=5))
inputs_latch_16neu.add(gdstk.Label('syn_addr_latched[3]', (91.805,-6.042), layer=67, texttype=5))
inputs_latch_16neu.add(gdstk.Label('neu_addr_latched[0]', (91.74,-13.772), layer=67, texttype=5))
inputs_latch_16neu.add(gdstk.Label('neu_addr_latched[1]', (91.795,-33.212), layer=67, texttype=5))
inputs_latch_16neu.add(gdstk.Label('neu_addr_latched[2]', (91.75,-35.587), layer=67, texttype=5))
inputs_latch_16neu.add(gdstk.Label('neu_addr_latched[3]', (91.78,-51.817), layer=67, texttype=5))
inputs_latch_16neu.add(gdstk.Label('neu_addr_in[3]', (82.652,-51.452), layer=68, texttype=5))
inputs_latch_16neu.add(gdstk.Label('syn_addr_in[2]', (82.712,2.917), layer=68, texttype=5))
inputs_latch_16neu.add(gdstk.Label('syn_addr_in[3]', (82.662,-6.372), layer=68, texttype=5))
inputs_latch_16neu.add(gdstk.Label('neu_addr_in[0]', (82.712,-13.397), layer=68, texttype=5))
inputs_latch_16neu.add(gdstk.Label('neu_addr_in[1]', (82.687,-33.597), layer=68, texttype=5))
inputs_latch_16neu.add(gdstk.Label('neu_addr_in[2]', (82.697,-35.212), layer=68, texttype=5))
inputs_latch_16neu.add(gdstk.Label('exc_in', (82.665,-73.16), layer=68, texttype=5))
inputs_latch_16neu.add(gdstk.Label('GND', (88.605,22.017), layer=69, texttype=5))
inputs_latch_16neu.add(gdstk.Label('VDD', (83.065,22.202), layer=69, texttype=5))
inputs_latch_16neu.add(gdstk.Label('req_in_array', (82.947,35.142), layer=68, texttype=5))
inputs_latch_16neu.add(gdstk.Label('exc_latched', (91.857,-73.675), layer=67, texttype=5))

lib.write_gds('inputs_latch_16neu.gds')
